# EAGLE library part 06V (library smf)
CONNECTOR

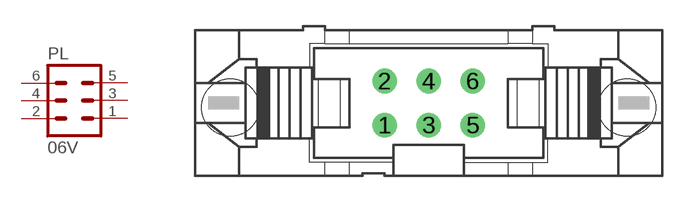
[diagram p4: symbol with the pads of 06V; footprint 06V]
Designator prefix PL

## 06V  [06V]
1  1  pas
2  2  pas
3  3  pas
4  4  pas
5  5  pas
6  6  pas

## Footprint 06V (pad centres in mm)
CONNECTOR
drill 0.914 round: 1 -2.54,-1.27; 2 -2.54,1.27; 3 0,-1.27; 4 0,1.27; 5 2.54,-1.27; 6 2.54,1.27
hole 3.302 at 11.43,-0.254
hole 3.302 at -11.43,-0.254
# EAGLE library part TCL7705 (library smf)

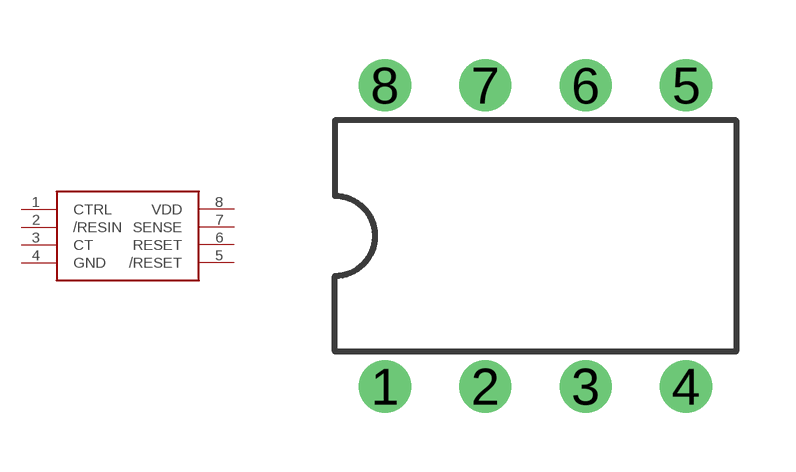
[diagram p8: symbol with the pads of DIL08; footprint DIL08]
Designator prefix -

## TCL7705  [DIL08]
1  CTRL  in
2  /RESIN  in
3  CT
4  GND  in
5  /RESET  out
6  RESET  out
7  SENSE  in
8  VDD  in

## Footprint DIL08 (pad centres in mm)
Dual In Line Package
drill 0.813 round: 1 -3.81,-3.81; 2 -1.27,-3.81; 3 1.27,-3.81; 4 3.81,-3.81; 5 3.81,3.81; 6 1.27,3.81; 7 -1.27,3.81; 8 -3.81,3.81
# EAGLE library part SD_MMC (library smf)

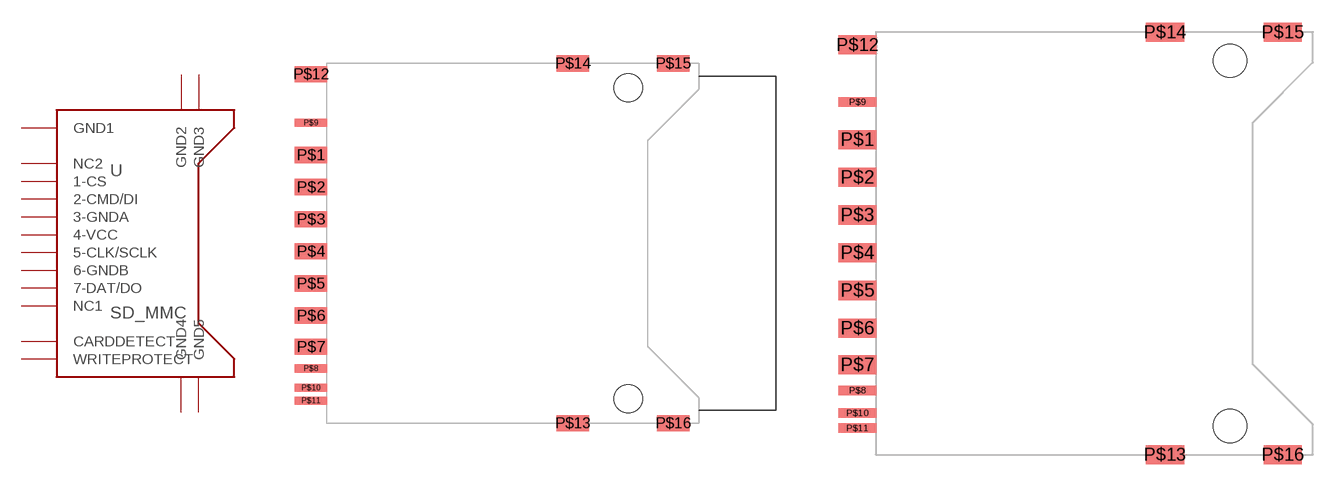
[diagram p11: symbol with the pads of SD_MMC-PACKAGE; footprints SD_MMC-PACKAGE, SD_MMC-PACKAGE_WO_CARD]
Designator prefix -

## SD_MMCW_CARD  [SD_MMC-PACKAGE]
P$1  1-CS
P$2  2-CMD/DI
P$3  3-GNDA  pwr
P$4  4-VCC  pwr
P$5  5-CLK/SCLK
P$6  6-GNDB  pwr
P$7  7-DAT/DO
P$8  NC1  nc
P$9  NC2  nc
P$10  CARDDETECT  out
P$11  WRITEPROTECT  out
P$12  GND1  pwr
P$13  GND2  pwr
P$14  GND3  pwr
P$15  GND4  pwr
P$16  GND5  pwr

## SD_MMCWO_CARD  [SD_MMC-PACKAGE_WO_CARD]
Pads as for SD_MMC-PACKAGE

## Footprint SD_MMC-PACKAGE (pad centres in mm)
smd 2.54 x 1.27: P$1 -0.2,20.88; P$2 -0.2,18.38; P$3 -0.2,15.88; P$4 -0.2,13.38; P$5 -0.2,10.88; P$6 -0.2,8.38; P$7 -0.2,5.95; P$12 -0.2,27.16; P$13 20.19,0; P$14 20.19,28; P$15 28,28; P$16 28,0
smd 2.54 x 0.635: P$8 -0.2,4.26; P$9 -0.2,23.38; P$10 -0.2,2.76; P$11 -0.2,1.76
hole 2.2 at 24.508,1.9
hole 2.2 at 24.508,26.1

## Footprint SD_MMC-PACKAGE_WO_CARD (pad centres in mm)
smd 2.54 x 1.27: P$1 -0.2,20.88; P$2 -0.2,18.38; P$3 -0.2,15.88; P$4 -0.2,13.38; P$5 -0.2,10.88; P$6 -0.2,8.38; P$7 -0.2,5.95; P$12 -0.2,27.16; P$13 20.19,0; P$14 20.19,28; P$15 28,28; P$16 28,0
smd 2.54 x 0.635: P$8 -0.2,4.26; P$9 -0.2,23.38; P$10 -0.2,2.76; P$11 -0.2,1.76
hole 2.2 at 24.508,1.9
hole 2.2 at 24.508,26.1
